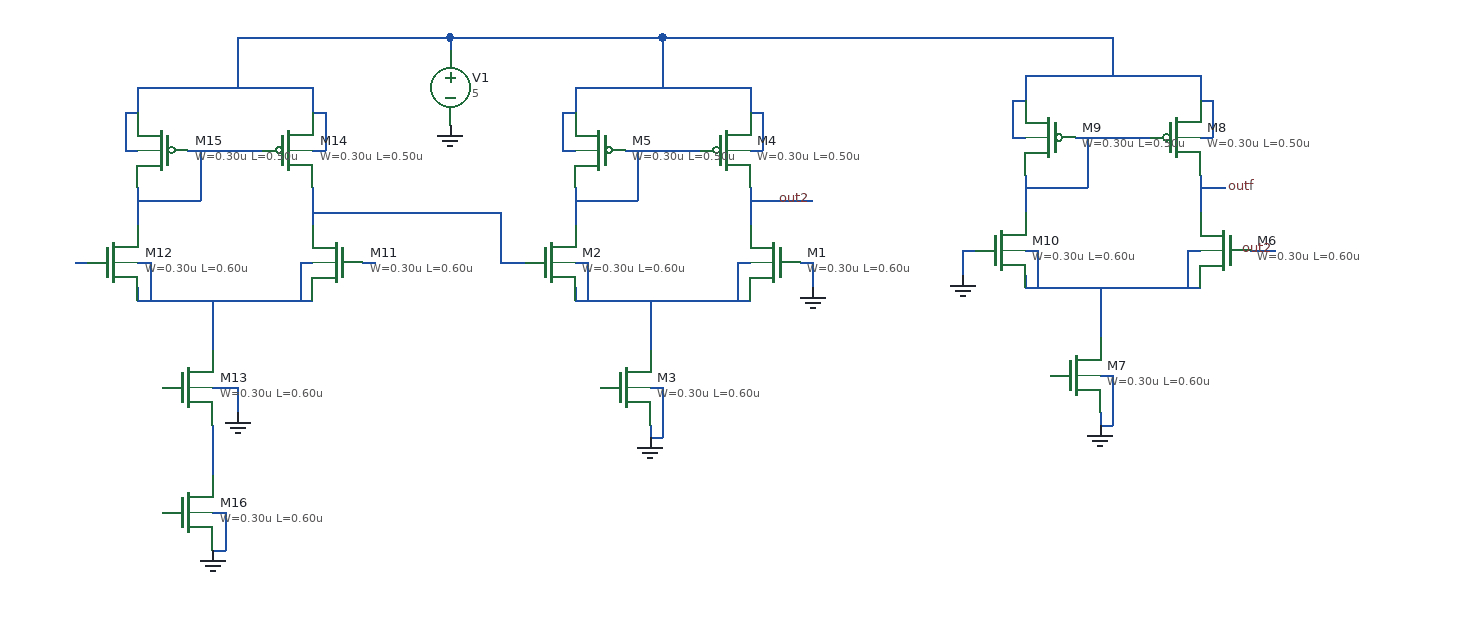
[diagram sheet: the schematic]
v {xschem version=3.4.8RC file_version=1.3}
G {}
K {}
V {}
S {}
F {}
E {}
N 40 -80 40 -70 {lab=#net1}
N 40 -70 160 -70 {lab=#net1}
N 100 -70 100 -30 {lab=#net1}
N 40 -100 50 -100 {lab=#net1}
N 50 -100 50 -70 {lab=#net1}
N 170 -100 180 -100 {lab=#net1}
N 170 -100 170 -70 {lab=#net1}
N 100 -0 110 0 {lab=0}
N 100 30 100 40 {lab=0}
N 110 -0 110 40 {lab=0}
N 100 40 110 40 {lab=0}
N 160 -70 180 -70 {lab=#net1}
N 30 -190 40 -190 {lab=#net2}
N 30 -220 30 -190 {lab=#net2}
N 30 -220 40 -220 {lab=#net2}
N 180 -190 190 -190 {lab=#net2}
N 190 -220 190 -190 {lab=#net2}
N 180 -220 190 -220 {lab=#net2}
N 40 -160 40 -130 {lab=#net3}
N 180 -160 180 -130 {lab=out2}
N 40 -240 40 -220 {lab=#net2}
N 40 -240 180 -240 {lab=#net2}
N 180 -240 180 -220 {lab=#net2}
N -60 -280 -60 -270 {lab=#net2}
N -60 -280 110 -280 {lab=#net2}
N 110 -280 110 -240 {lab=#net2}
N 80 -190 140 -190 {lab=#net3}
N 90 -190 90 -180 {lab=#net3}
N 90 -180 90 -170 {lab=#net3}
N 90 -170 90 -160 {lab=#net3}
N 90 -160 90 -150 {lab=#net3}
N 40 -150 90 -150 {lab=#net3}
N 400 -90 400 -80 {lab=#net4}
N 400 -80 520 -80 {lab=#net4}
N 460 -80 460 -40 {lab=#net4}
N 400 -110 410 -110 {lab=#net4}
N 410 -110 410 -80 {lab=#net4}
N 530 -110 540 -110 {lab=#net4}
N 530 -110 530 -80 {lab=#net4}
N 460 -10 470 -10 {lab=0}
N 460 20 460 30 {lab=0}
N 470 -10 470 30 {lab=0}
N 460 30 470 30 {lab=0}
N 520 -80 540 -80 {lab=#net4}
N 390 -200 400 -200 {lab=#net2}
N 390 -230 390 -200 {lab=#net2}
N 390 -230 400 -230 {lab=#net2}
N 540 -200 550 -200 {lab=#net2}
N 550 -230 550 -200 {lab=#net2}
N 540 -230 550 -230 {lab=#net2}
N 400 -170 400 -140 {lab=#net5}
N 540 -170 540 -140 {lab=outf}
N 400 -250 400 -230 {lab=#net2}
N 400 -250 540 -250 {lab=#net2}
N 540 -250 540 -230 {lab=#net2}
N 440 -200 500 -200 {lab=#net5}
N 450 -200 450 -190 {lab=#net5}
N 450 -190 450 -180 {lab=#net5}
N 450 -180 450 -170 {lab=#net5}
N 450 -170 450 -160 {lab=#net5}
N 400 -160 450 -160 {lab=#net5}
N 110 -280 470 -280 {lab=#net2}
N 470 -280 470 -250 {lab=#net2}
N -310 -80 -310 -70 {lab=#net6}
N -310 -70 -190 -70 {lab=#net6}
N -250 -70 -250 -30 {lab=#net6}
N -310 -100 -300 -100 {lab=#net6}
N -300 -100 -300 -70 {lab=#net6}
N -180 -100 -170 -100 {lab=#net6}
N -180 -100 -180 -70 {lab=#net6}
N -250 0 -240 0 {lab=0}
N -250 30 -250 40 {lab=#net7}
N -190 -70 -170 -70 {lab=#net6}
N -320 -190 -310 -190 {lab=#net2}
N -320 -220 -320 -190 {lab=#net2}
N -320 -220 -310 -220 {lab=#net2}
N -170 -190 -160 -190 {lab=#net2}
N -160 -220 -160 -190 {lab=#net2}
N -170 -220 -160 -220 {lab=#net2}
N -310 -160 -310 -130 {lab=#net8}
N -170 -160 -170 -130 {lab=#net9}
N -310 -240 -310 -220 {lab=#net2}
N -310 -240 -170 -240 {lab=#net2}
N -170 -240 -170 -220 {lab=#net2}
N -270 -190 -210 -190 {lab=#net8}
N -260 -190 -260 -180 {lab=#net8}
N -260 -180 -260 -170 {lab=#net8}
N -260 -170 -260 -160 {lab=#net8}
N -260 -160 -260 -150 {lab=#net8}
N -310 -150 -260 -150 {lab=#net8}
N -230 -280 -60 -280 {lab=#net2}
N -230 -280 -230 -240 {lab=#net2}
N -250 30 -250 70 {lab=#net7}
N -250 100 -240 100 {lab=0}
N -240 100 -240 130 {lab=0}
N -250 130 -240 130 {lab=0}
N -130 -100 -120 -100 {lab=#net10}
N -10 -100 0 -100 {lab=#net9}
N 220 -100 230 -100 {lab=0}
N -20 -100 -10 -100 {lab=#net9}
N -20 -140 -20 -100 {lab=#net9}
N -170 -140 -20 -140 {lab=#net9}
N 230 -100 230 -80 {lab=0}
N 180 -150 230 -150 {lab=out2}
N -240 -0 -230 0 {lab=0}
N -230 -0 -230 20 {lab=0}
N 580 -110 600 -110 {lab=out2}
N 550 -160 560 -160 {lab=outf}
N 540 -160 550 -160 {lab=outf}
N 350 -110 360 -110 {lab=0}
N 350 -110 350 -90 {lab=0}
N -360 -100 -350 -100 {lab=#net11}
C {symbols/nfet_05v0.sym} 200 -100 0 1 {name=M1
L=0.60u
W=0.30u
nf=1
m=1
ad="'int((nf+1)/2) * W/nf * 0.18u'"
pd="'2*int((nf+1)/2) * (W/nf + 0.18u)'"
as="'int((nf+2)/2) * W/nf * 0.18u'"
ps="'2*int((nf+2)/2) * (W/nf + 0.18u)'"
nrd="'0.18u / W'" nrs="'0.18u / W'"
sa=0 sb=0 sd=0
model=nfet_05v0
spiceprefix=X
}
C {symbols/nfet_05v0.sym} 20 -100 0 0 {name=M2
L=0.60u
W=0.30u
nf=1
m=1
ad="'int((nf+1)/2) * W/nf * 0.18u'"
pd="'2*int((nf+1)/2) * (W/nf + 0.18u)'"
as="'int((nf+2)/2) * W/nf * 0.18u'"
ps="'2*int((nf+2)/2) * (W/nf + 0.18u)'"
nrd="'0.18u / W'" nrs="'0.18u / W'"
sa=0 sb=0 sd=0
model=nfet_05v0
spiceprefix=X
}
C {symbols/nfet_05v0.sym} 80 0 0 0 {name=M3
L=0.60u
W=0.30u
nf=1
m=1
ad="'int((nf+1)/2) * W/nf * 0.18u'"
pd="'2*int((nf+1)/2) * (W/nf + 0.18u)'"
as="'int((nf+2)/2) * W/nf * 0.18u'"
ps="'2*int((nf+2)/2) * (W/nf + 0.18u)'"
nrd="'0.18u / W'" nrs="'0.18u / W'"
sa=0 sb=0 sd=0
model=nfet_05v0
spiceprefix=X
}
C {gnd.sym} 100 40 0 0 {name=l1 lab=0}
C {symbols/pfet_05v0.sym} 160 -190 0 0 {name=M4
L=0.50u
W=0.30u
nf=1
m=1
ad="'int((nf+1)/2) * W/nf * 0.18u'"
pd="'2*int((nf+1)/2) * (W/nf + 0.18u)'"
as="'int((nf+2)/2) * W/nf * 0.18u'"
ps="'2*int((nf+2)/2) * (W/nf + 0.18u)'"
nrd="'0.18u / W'" nrs="'0.18u / W'"
sa=0 sb=0 sd=0
model=pfet_05v0
spiceprefix=X
}
C {symbols/pfet_05v0.sym} 60 -190 0 1 {name=M5
L=0.50u
W=0.30u
nf=1
m=1
ad="'int((nf+1)/2) * W/nf * 0.18u'"
pd="'2*int((nf+1)/2) * (W/nf + 0.18u)'"
as="'int((nf+2)/2) * W/nf * 0.18u'"
ps="'2*int((nf+2)/2) * (W/nf + 0.18u)'"
nrd="'0.18u / W'" nrs="'0.18u / W'"
sa=0 sb=0 sd=0
model=pfet_05v0
spiceprefix=X
}
C {vsource.sym} -60 -240 0 0 {name=V1 value=5 savecurrent=false}
C {gnd.sym} -60 -210 0 0 {name=l2 lab=0}
C {symbols/nfet_05v0.sym} 560 -110 0 1 {name=M6
L=0.60u
W=0.30u
nf=1
m=1
ad="'int((nf+1)/2) * W/nf * 0.18u'"
pd="'2*int((nf+1)/2) * (W/nf + 0.18u)'"
as="'int((nf+2)/2) * W/nf * 0.18u'"
ps="'2*int((nf+2)/2) * (W/nf + 0.18u)'"
nrd="'0.18u / W'" nrs="'0.18u / W'"
sa=0 sb=0 sd=0
model=nfet_05v0
spiceprefix=X
}
C {symbols/nfet_05v0.sym} 440 -10 0 0 {name=M7
L=0.60u
W=0.30u
nf=1
m=1
ad="'int((nf+1)/2) * W/nf * 0.18u'"
pd="'2*int((nf+1)/2) * (W/nf + 0.18u)'"
as="'int((nf+2)/2) * W/nf * 0.18u'"
ps="'2*int((nf+2)/2) * (W/nf + 0.18u)'"
nrd="'0.18u / W'" nrs="'0.18u / W'"
sa=0 sb=0 sd=0
model=nfet_05v0
spiceprefix=X
}
C {gnd.sym} 460 30 0 0 {name=l3 lab=0}
C {symbols/pfet_05v0.sym} 520 -200 0 0 {name=M8
L=0.50u
W=0.30u
nf=1
m=1
ad="'int((nf+1)/2) * W/nf * 0.18u'"
pd="'2*int((nf+1)/2) * (W/nf + 0.18u)'"
as="'int((nf+2)/2) * W/nf * 0.18u'"
ps="'2*int((nf+2)/2) * (W/nf + 0.18u)'"
nrd="'0.18u / W'" nrs="'0.18u / W'"
sa=0 sb=0 sd=0
model=pfet_05v0
spiceprefix=X
}
C {symbols/pfet_05v0.sym} 420 -200 0 1 {name=M9
L=0.50u
W=0.30u
nf=1
m=1
ad="'int((nf+1)/2) * W/nf * 0.18u'"
pd="'2*int((nf+1)/2) * (W/nf + 0.18u)'"
as="'int((nf+2)/2) * W/nf * 0.18u'"
ps="'2*int((nf+2)/2) * (W/nf + 0.18u)'"
nrd="'0.18u / W'" nrs="'0.18u / W'"
sa=0 sb=0 sd=0
model=pfet_05v0
spiceprefix=X
}
C {symbols/nfet_05v0.sym} 380 -110 0 0 {name=M10
L=0.60u
W=0.30u
nf=1
m=1
ad="'int((nf+1)/2) * W/nf * 0.18u'"
pd="'2*int((nf+1)/2) * (W/nf + 0.18u)'"
as="'int((nf+2)/2) * W/nf * 0.18u'"
ps="'2*int((nf+2)/2) * (W/nf + 0.18u)'"
nrd="'0.18u / W'" nrs="'0.18u / W'"
sa=0 sb=0 sd=0
model=nfet_05v0
spiceprefix=X
}
C {symbols/nfet_05v0.sym} -150 -100 0 1 {name=M11
L=0.60u
W=0.30u
nf=1
m=1
ad="'int((nf+1)/2) * W/nf * 0.18u'"
pd="'2*int((nf+1)/2) * (W/nf + 0.18u)'"
as="'int((nf+2)/2) * W/nf * 0.18u'"
ps="'2*int((nf+2)/2) * (W/nf + 0.18u)'"
nrd="'0.18u / W'" nrs="'0.18u / W'"
sa=0 sb=0 sd=0
model=nfet_05v0
spiceprefix=X
}
C {symbols/nfet_05v0.sym} -330 -100 0 0 {name=M12
L=0.60u
W=0.30u
nf=1
m=1
ad="'int((nf+1)/2) * W/nf * 0.18u'"
pd="'2*int((nf+1)/2) * (W/nf + 0.18u)'"
as="'int((nf+2)/2) * W/nf * 0.18u'"
ps="'2*int((nf+2)/2) * (W/nf + 0.18u)'"
nrd="'0.18u / W'" nrs="'0.18u / W'"
sa=0 sb=0 sd=0
model=nfet_05v0
spiceprefix=X
}
C {symbols/nfet_05v0.sym} -270 0 0 0 {name=M13
L=0.60u
W=0.30u
nf=1
m=1
ad="'int((nf+1)/2) * W/nf * 0.18u'"
pd="'2*int((nf+1)/2) * (W/nf + 0.18u)'"
as="'int((nf+2)/2) * W/nf * 0.18u'"
ps="'2*int((nf+2)/2) * (W/nf + 0.18u)'"
nrd="'0.18u / W'" nrs="'0.18u / W'"
sa=0 sb=0 sd=0
model=nfet_05v0
spiceprefix=X
}
C {symbols/pfet_05v0.sym} -190 -190 0 0 {name=M14
L=0.50u
W=0.30u
nf=1
m=1
ad="'int((nf+1)/2) * W/nf * 0.18u'"
pd="'2*int((nf+1)/2) * (W/nf + 0.18u)'"
as="'int((nf+2)/2) * W/nf * 0.18u'"
ps="'2*int((nf+2)/2) * (W/nf + 0.18u)'"
nrd="'0.18u / W'" nrs="'0.18u / W'"
sa=0 sb=0 sd=0
model=pfet_05v0
spiceprefix=X
}
C {symbols/pfet_05v0.sym} -290 -190 0 1 {name=M15
L=0.50u
W=0.30u
nf=1
m=1
ad="'int((nf+1)/2) * W/nf * 0.18u'"
pd="'2*int((nf+1)/2) * (W/nf + 0.18u)'"
as="'int((nf+2)/2) * W/nf * 0.18u'"
ps="'2*int((nf+2)/2) * (W/nf + 0.18u)'"
nrd="'0.18u / W'" nrs="'0.18u / W'"
sa=0 sb=0 sd=0
model=pfet_05v0
spiceprefix=X
}
C {symbols/nfet_05v0.sym} -270 100 0 0 {name=M16
L=0.60u
W=0.30u
nf=1
m=1
ad="'int((nf+1)/2) * W/nf * 0.18u'"
pd="'2*int((nf+1)/2) * (W/nf + 0.18u)'"
as="'int((nf+2)/2) * W/nf * 0.18u'"
ps="'2*int((nf+2)/2) * (W/nf + 0.18u)'"
nrd="'0.18u / W'" nrs="'0.18u / W'"
sa=0 sb=0 sd=0
model=nfet_05v0
spiceprefix=X
}
C {gnd.sym} -250 130 0 0 {name=l4 lab=0}
C {gnd.sym} -230 20 0 0 {name=l5 lab=0}
C {gnd.sym} 230 -80 0 0 {name=l6 lab=0}
C {lab_wire.sym} 230 -150 0 0 {name=p1 sig_type=std_logic lab=out2
}
C {lab_wire.sym} 600 -110 0 0 {name=p2 sig_type=std_logic lab=out2
}
C {lab_wire.sym} 560 -160 0 1 {name=p3 sig_type=std_logic lab=outf
}
C {gnd.sym} 350 -90 0 0 {name=l7 lab=0}
